VERSION 5.8 ;
BUSBITCHARS "[]" ;
DIVIDERCHAR "/" ;
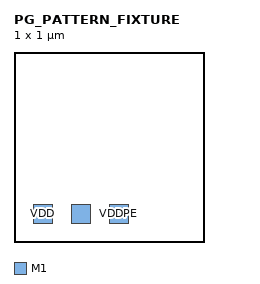
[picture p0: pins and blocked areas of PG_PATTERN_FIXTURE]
MACRO PG_PATTERN_FIXTURE
  CLASS CORE ;
  ORIGIN 0 0 ;
  SIZE 1 BY 1 ;
  SYMMETRY X Y ;
  PIN VDD
    DIRECTION INOUT ;
    USE POWER ;
    PORT
      LAYER M1 ;
      RECT 0.1 0.1 0.2 0.2 ;
    END
  END VDD
  PIN VDDCE
    DIRECTION INOUT ;
    USE POWER ;
    PORT
      LAYER M1 ;
      RECT 0.3 0.1 0.4 0.2 ;
    END
  END VDDCE
  PIN VDDPE
    DIRECTION INOUT ;
    USE POWER ;
    PORT
      LAYER M1 ;
      RECT 0.5 0.1 0.6 0.2 ;
    END
  END VDDPE
END PG_PATTERN_FIXTURE
END LIBRARY
